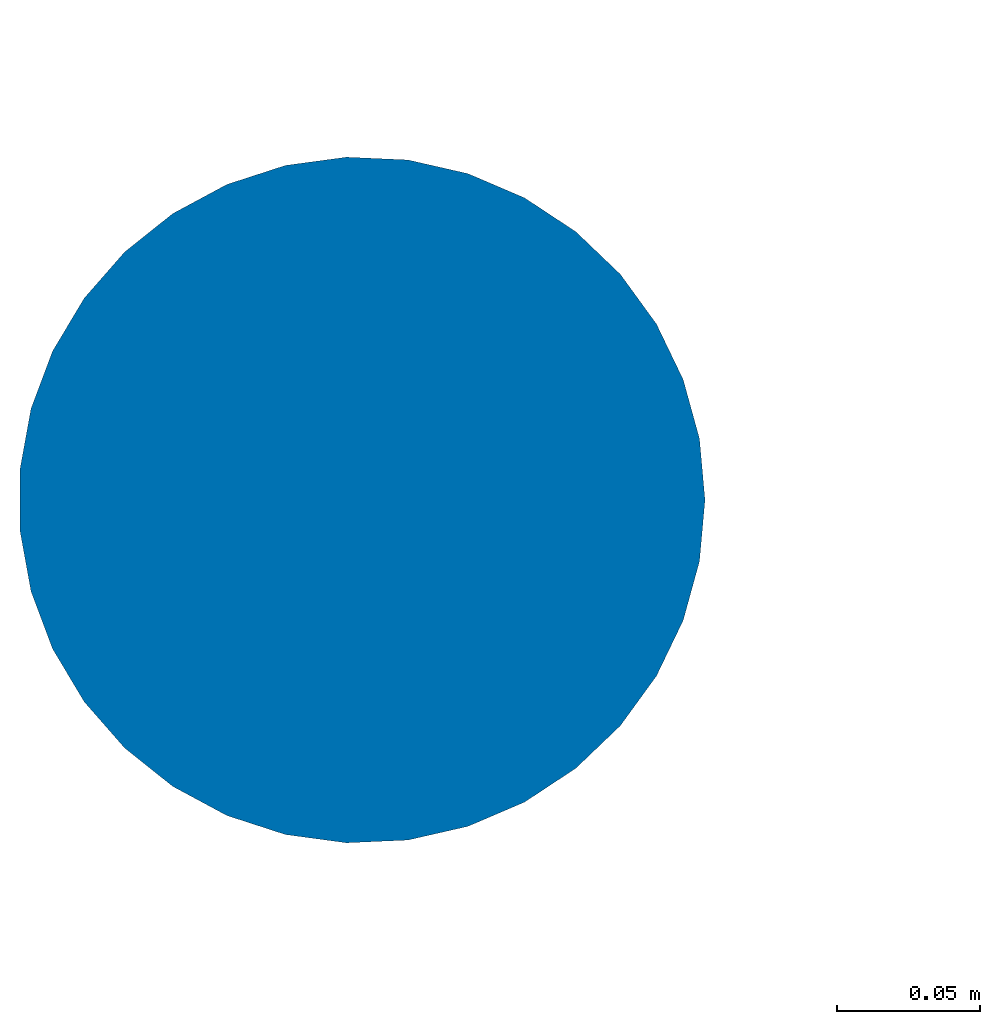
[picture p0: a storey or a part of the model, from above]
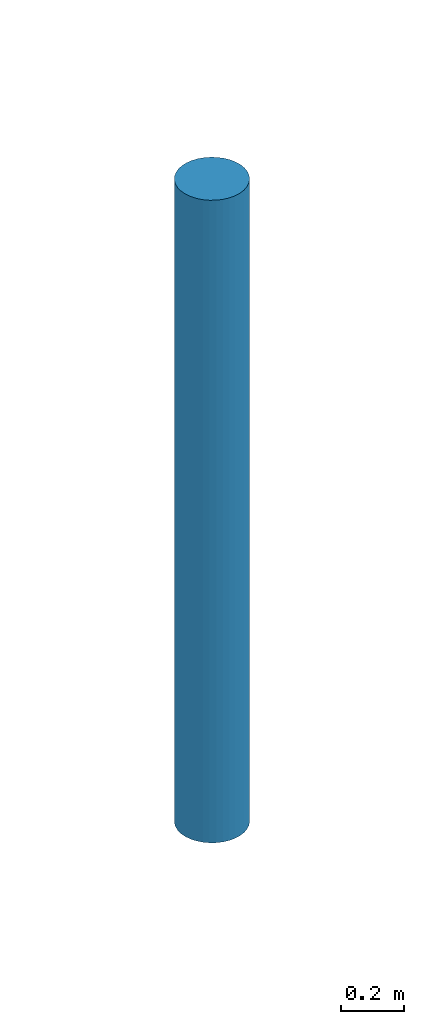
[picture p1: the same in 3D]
Properties of the parts of a building model (IFC2X3)

# File
Description: ViewDefinition [CoordinationView_V2.0, SpaceBoundary2ndLevelAddOnView], Option [Drawing Scale: 100.000000], Option [Elements to export: Visible elements (on all stories)], Option [Partial Structure Display: Entire Model], Option [IFC Domain: All], Option [Structural Function: All Elements], Option [Convert Grid elements: On], Option [Convert IFC Annotations and ARCHICAD 2D elements: Off], Option [Convert 2D symbols of Doors and Windows: Off], Option [Export geometries that Participates in Collision Detection only: Off], Option [Split complex elements: On], Option [IFC Domain For Space Containment: Custom], Option [Elements in Solid Element Operations: Extruded/revolved], Option [Elements with junctions: Extruded/revolved without junctions], Option [Slabs with slanted edge(s): Extruded], Option [IFC Site Location: At Project Origin], Option [Curtain Wall export mode: Container Element], Option [Railing export mode: Container Element], Option [Stair export mode: Container Element], Option [Properties To Export: All properties], Option [Space containment: Off], Option [Bounding Box: Off], Option [Geometry to type objects: Off], Option [Element Properties: Visible Only], Option [Building Material Properties: Off], Option [Element Parameters: Off], Option [Component Parameters: Off], Option [IFC Base Quantities: Off], Option [Door Window Parameters: On], Option [IFC Space boundaries: On], Option [ARCHICAD Zone Categories as IFC Space classification data: Off], Option [Element Classifications: On]
File name: K:\09-Projektid\3_PÕHIPROJEKT\00_Asendiplaanid\IFC\283_PP_AS_IFC_12.04.2021.ifc
Time: 2021-04-12T10:08:18
Author: Kontakti Täisnimi
Organization: Building Designer Office
Written by: The EXPRESS Data Manager Version 5.02.0100.09 : 26 Sep 2013
Made in: IFC file generated by GRAPHISOFT ARCHICAD 23.0.0 INT FULL Windows version (IFC add-on version: 4006 INT FULL).
Authorization: Kontakti Täisnimi

# IfcSite, Politse- ja Piirivalveameti ning Päästeameti ühishoone
Description: Kinnistu Kirjeldus; RefLatitude: 59, 26, 0, 0; RefLongitude: 24, 45, 0, 0; RefElevation: 0 mm; Classification: 1.0.1 IfcSite (kinnistu) (RKAS BIM + ARCHICAD Classification 23 + v 2.0)
AR_Kinnistu - 020_Pindala: 15638 m2; 025_Max_kõrgus: 18000 mm; 015_Ehitatav_pindala: 5500 m2; 010_Katastritunnus: 32213:001:0035 ja 32213:001:0036

# IfcBuilding, Politse- ja Piirivalveameti ning Päästeameti ühishoone
Classification: 1.0.2 IfcBuilding (hoone) (RKAS BIM + ARCHICAD Classification 23 + v 2.0)
AR_Hoone - 035_Sprinkler: no; 030_Hoone_aadress: Kohtla-Järve Järveküla tee 40 ja 40c; 040_Kõrgus: 8800 mm; 050_Neto_pindala: 2293.7 m2; 055_Neto_ruumala: 13540.2 m3; ?: 1820.8 m2; 001_Nimetus: Politse- ja Piirivalveameti ning Päästeameti ühishoone

# IfcBuildingStorey (2)
In: Politse- ja Piirivalveameti ning Päästeameti ühishoone
Name | Elevation (mm) | 060_Korruse_nimi | 065_Korruse_number | 070_Maapealne
Vundament | -4000 | Vundament | -1 | no
Esimene korrus | 0 | Esimene korrus | 1 | yes | Classification: 1.0.3 IfcBuildingStorey (korrus) (RKAS BIM + ARCHICAD Classification 23 + v 2.0)

# IfcBuildingElementProxy: Betoon 1200 (7)
In: Esimene korrus
Material: Betoon
AC_Pset_RenovationAndPhasing - Renovation Status: New

# IfcBuildingElementProxy: Betoon 2100, PIIRDEAED
In: Esimene korrus
Material: Betoon
AC_Pset_RenovationAndPhasing - Renovation Status: New

# IfcBuildingElementProxy: Bollard 23 (3)
In: Esimene korrus
AC_Pset_RenovationAndPhasing - Renovation Status: New

# IfcBuildingElementProxy: Door 23 (2)
In: Esimene korrus
AC_Pset_RenovationAndPhasing - Renovation Status: New

# IfcBuildingElementProxy: Grass Model 23 (64)
In: Esimene korrus
AC_Pset_RenovationAndPhasing - Renovation Status: New

# IfcBuildingElementProxy: IfcBuildingElementProxy (43149)
In: Esimene korrus
Name | Classification | Material | Renovation Status
39 x PIIRDE POST - 001 | 1.11 IfcRailing (piire) (_RKAS BIM + ARCHICAD Classification) | Teras - Konstruktsioon | Existing
77 x PIIRDE OSA - 001 | 1.11 IfcRailing (piire) (_RKAS BIM + ARCHICAD Classification) | Teras - Konstruktsioon | Existing
10760 x BALUSTER - 001 | 1.11 IfcRailing (piire) (_RKAS BIM + ARCHICAD Classification) | Teras - Konstruktsioon | Existing
126 x SISEPOST - 001 | 1.11 IfcRailing (piire) (_RKAS BIM + ARCHICAD Classification) | ET-03_Raud | Existing
44 x RAIL CONNECTION - 001 | Rail (ARCHICAD Classification) | ET-03_Raud | Existing
121 x PIIRDE OSA - 001 | 1.11 IfcRailing (piire) (_RKAS BIM + ARCHICAD Classification) | ET-03_Raud | Existing
30448 x BALUSTER - 001 | 1.11 IfcRailing (piire) (_RKAS BIM + ARCHICAD Classification) | ET-03_Raud | Existing
ÜL PIIRE - 001 | 1.11 IfcRailing (piire) (_RKAS BIM + ARCHICAD Classification) | Teras - Konstruktsioon | New
1408 x BALUSTER - 001 | 1.11 IfcRailing (piire) (_RKAS BIM + ARCHICAD Classification) | ET-06_Teras - Konstruktsioon | Existing
51 x RAIL CONNECTION - 001 | Rail (ARCHICAD Classification) | Teras - Konstruktsioon | Existing
41 x SISEPOST - 001 | 1.11 IfcRailing (piire) (_RKAS BIM + ARCHICAD Classification) | Teras - Konstruktsioon | Existing
PIIRDE OSA - 001 | 1.11 IfcRailing (piire) (_RKAS BIM + ARCHICAD Classification) | Raud | Existing
13 x RAIL CONNECTION - 001 | Rail (ARCHICAD Classification) | Iron | Existing
13 x PIIRDE OSA - 001 | 1.11 IfcRailing (piire) (_RKAS BIM + ARCHICAD Classification) | Iron | Existing
2 x HANDRAIL END - 001 | Rail (ARCHICAD Classification) | Teras - Konstruktsioon | New
2 x HANDRAIL END - 002 | Rail (ARCHICAD Classification) | Teras - Konstruktsioon | New
2 x KÄSIPUU - 001 | 1.11 IfcRailing (piire) (_RKAS BIM + ARCHICAD Classification) | Teras - Konstruktsioon | Existing

# IfcBuildingElementProxy: Landscaping_Outdoor-Furniture_CYKLOS_KAPPA-Cycle-Shelter-4-5m-8-bicycles-Sedu, VÄLISREDEL
In: Esimene korrus
AC_Pset_RenovationAndPhasing - Renovation Status: New

# IfcBuildingElementProxy: Molok Classic_ (4)
In: Esimene korrus
AC_Pset_RenovationAndPhasing - Renovation Status: New

# IfcBuildingElementProxy: Outdoor Bench 23 (2)
In: Esimene korrus
AC_Pset_RenovationAndPhasing - Renovation Status: New

# IfcBuildingElementProxy: Parking Place 23 (8)
In: Esimene korrus
AC_Pset_RenovationAndPhasing - Renovation Status: New
Name
7 x PARKIMISJOONED
PARKIMISJOON

# IfcBuildingElementProxy: Pine Tree Model 23 (14)
In: Esimene korrus
AC_Pset_RenovationAndPhasing - Renovation Status: New
Name
13 x ELUPUU
VÄLISREDEL

# IfcBuildingElementProxy: Railing Type (14)
In: Esimene korrus
AC_Pset_RenovationAndPhasing - Renovation Status: New
Name
11 x PIIRDEAED
LIUGVÄRAV
2 x KENNELI PIIRE

# IfcBuildingElementProxy: SKR-04_Puitplaat 1200 (2)
In: Esimene korrus
Material: SKR-04_Puitplaat
AC_Pset_RenovationAndPhasing - Renovation Status: New

# IfcBuildingElementProxy: Sliding Folding Multipanel Bifold Door 23 (3)
In: Esimene korrus
AC_Pset_RenovationAndPhasing - Renovation Status: New

# IfcBuildingElementProxy: Sports-Recreation_Gym-Equipment-Indoor_Draper-Inc_CM-Column-Mounted-Stationary-Basketball, Korvpallilaud
In: Esimene korrus
Classification: 1.02 IfcBuildingElementProxyType (objekt) (RKAS BIM + ARCHICAD Classification)
AR_Aken - 355_Pindala: 0 m2
Pset_BuildingElementProxyCommon - Reference: Sports-Recreation_Gym-Equipment-Indoor_Draper-Inc_CM-Column-Mounted-Stationary-Basketball
AR_001-002 - 002_Tüüp: Sports-Recreation_Gym-Equipment-Indoor_Draper-Inc_CM-Column-Mounted-Stationary-Basketball
AC_Pset_RenovationAndPhasing - Renovation Status: New

# IfcBuildingElementProxy: Tree Model Simple 1 23 (23)
In: Esimene korrus
AC_Pset_RenovationAndPhasing - Renovation Status: New

# IfcBuildingElementProxy: VKK-00_GENEERILINE - VÄLINE KESKKOND (76)
In: Esimene korrus
Material: VKK-00_GENEERILINE - VÄLINE KESKKOND
AC_Pset_RenovationAndPhasing - Renovation Status: New
Name
2 x MURU
9 x MAAPIND
5 x BETOONKIVI
30 x ÄÄREKIVI
4 x HALJASTUSKONTEINER
4 x KASVUPINNAS
4 x BETOONISTE
13 x BETOONTAKISTUS
ASFALT
Betoonäär
BETOONIST PESUPLATS
2 x TARTAAN

# IfcBuildingElementProxy: VKK-00_GENEERILINE - VÄLINE KESKKOND 20200, KÕRVALHOONE
In: Esimene korrus
Material: VKK-00_GENEERILINE - VÄLINE KESKKOND
AC_Pset_RenovationAndPhasing - Renovation Status: New

# IfcBuildingElementProxy: VKK-00_GENEERILINE - VÄLINE KESKKOND 3500, KÕRVALHOONE
In: Esimene korrus
Material: VKK-00_GENEERILINE - VÄLINE KESKKOND
AC_Pset_RenovationAndPhasing - Renovation Status: New

# IfcBuildingElementProxy: VKK-00_GENEERILINE - VÄLINE KESKKOND 6000, KÕRVALHOONE
In: Esimene korrus
Material: VKK-00_GENEERILINE - VÄLINE KESKKOND
AC_Pset_RenovationAndPhasing - Renovation Status: New

# IfcBuildingElementProxy: VKK-00_GENEERILINE - VÄLINE KESKKOND 7000, KÕRVALHOONE
In: Esimene korrus
Material: VKK-00_GENEERILINE - VÄLINE KESKKOND
AC_Pset_RenovationAndPhasing - Renovation Status: New

# IfcBuildingElementProxy: VKK-00_GENEERILINE - VÄLINE KESKKOND 750 (2)
In: Esimene korrus
Material: VKK-00_GENEERILINE - VÄLINE KESKKOND
AC_Pset_RenovationAndPhasing - Renovation Status: New

# IfcBuildingElementProxy: VKK-00_GENEERILINE - VÄLINE KESKKOND 889, KÕRVALMAAPIND
In: Esimene korrus
Material: VKK-00_GENEERILINE - VÄLINE KESKKOND
AC_Pset_RenovationAndPhasing - Renovation Status: New

# IfcColumn: ET-05_Teras D240, POST
In: Vundament
Type - PredefinedType: COLUMN
Classification: 1.03 IfcColumnType (post) (RKAS BIM + ARCHICAD Classification); Material: ET-05_Teras
Pset_ColumnCommon - Reference: ET-05; Slope: 90 deg; LoadBearing: yes; IsExternal: no
AR_001-002 - 002_Tüüp: ET-05
AC_Pset_RenovationAndPhasing - Renovation Status: New

# IfcDiscreteAccessory: Flat Panel TV 23, LED-EKRAAN
In: Esimene korrus
Classification: 1.09 IfcDiscreteAccessoryType (tarvik) (RKAS BIM + ARCHICAD Classification)
AR_001-002 - 002_Tüüp: Flat Panel TV
Pset_QuantityTakeOff - Reference: Flat Panel TV
AC_Pset_RenovationAndPhasing - Renovation Status: New

# IfcFurnishingElement: ET-05_Teras 70 x 70 (2)
In: Esimene korrus
Classification: 1.11 IfcFurnitureType (mööbel) (RKAS BIM + ARCHICAD Classification); Material: ET-05_Teras
AC_Pset_RenovationAndPhasing - Renovation Status: New

# IfcFurnishingElement: SV-00_GENEERILINE - SISEMINE VOODER 600, Tumba
In: Esimene korrus
Classification: 1.11 IfcFurnitureType (mööbel) (RKAS BIM + ARCHICAD Classification); Material: SV-00_GENEERILINE - SISEMINE VOODER
AR_Katus - 520_Pindala: 0 m2
AC_Pset_RenovationAndPhasing - Renovation Status: New

# IfcWallStandardCase: KON-00_GENEERILINE - KONSTRUKTSIOON 150, SS-01
In: Vundament
Classification: 1.24 IfcWallType (sein) (RKAS BIM + ARCHICAD Classification); Material: KON-00_GENEERILINE - KONSTRUKTSIOON 150 mm
AR_Sein - 340_Soojusläbivus: 0; 205_Tüüp: KON-00; 325_Helipidavus: R'w= 55 dB; 330_Tulekindlus: nõudeid ei esitata; 335_Välispiire: no; 376_Viimistlus_väljast: välis pind: Paint - Glossy White; sisepind: Paint - Glossy White; 505_Paksus: 150 mm; 605_Neto_pindala: 93.5637 m2; 600_Bruto_pindala: 93.5637 m2; 500_Kandev: FALSE; 376_Viimistlus_väljast (MUDELIS): KON-00_GENEERILINE - KONSTRUKTSIOON
Pset_WallCommon - Reference: KON-00; LoadBearing: no; IsExternal: no
AC_Pset_RenovationAndPhasing - Renovation Status: New

# IfcWallStandardCase: KON-00_GENEERILINE - KONSTRUKTSIOON 190 (2)
In: Esimene korrus
Classification: 1.24 IfcWallType (sein) (RKAS BIM + ARCHICAD Classification); Material: KON-00_GENEERILINE - KONSTRUKTSIOON 190 mm
Pset_WallCommon - Reference: KON-00; LoadBearing: yes; IsExternal: yes
AR_Sein - 205_Tüüp: KON-00; 325_Helipidavus: nõuded ei esitata; 330_Tulekindlus: nõudeid ei esitata; 335_Välispiire: yes; 505_Paksus: 190 mm; 500_Kandev: TRUE; 376_Viimistlus_väljast (MUDELIS): KON-00_GENEERILINE - KONSTRUKTSIOON
AC_Pset_RenovationAndPhasing - Renovation Status: New
Name | 376_Viimistlus_väljast | 605_Neto_pindala (m2) | 600_Bruto_pindala (m2)
Välissein | välis pind: RAL 010 20 10; sisepind: RAL 010 20 10 | 2.46654 | 16.0467
Välissein | välis pind: Paint - Glossy White; sisepind: Paint - Glossy White | 0 | 1.36202

# IfcWallStandardCase: KON-00_GENEERILINE - KONSTRUKTSIOON 80, Välissein
In: Esimene korrus
Classification: 1.24 IfcWallType (sein) (RKAS BIM + ARCHICAD Classification); Material: KON-00_GENEERILINE - KONSTRUKTSIOON 80 mm
Pset_WallCommon - Reference: KON-00; LoadBearing: yes; IsExternal: yes
AR_Sein - 205_Tüüp: KON-00; 325_Helipidavus: nõuded ei esitata; 330_Tulekindlus: nõudeid ei esitata; 335_Välispiire: yes; 376_Viimistlus_väljast: välis pind: Paint - Glossy White; sisepind: Paint - Glossy White; 505_Paksus: 80 mm; 605_Neto_pindala: 0.000242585 m2; 600_Bruto_pindala: 1.02525 m2; 500_Kandev: TRUE; 376_Viimistlus_väljast (MUDELIS): KON-00_GENEERILINE - KONSTRUKTSIOON
AC_Pset_RenovationAndPhasing - Renovation Status: New

# IfcWallStandardCase: SS-03_Sisesein 190 190 (2)
In: Esimene korrus
Classification: 1.24 IfcWallType (sein) (RKAS BIM + ARCHICAD Classification); Material: KON-05_Betoon Plokk - Konstuktsioon 190 mm
Pset_WallCommon - Reference: SS-03; LoadBearing: yes; IsExternal: yes
AR_Sein - 205_Tüüp: SS-03; 325_Helipidavus: nõuded ei esitata; 330_Tulekindlus: nõudeid ei esitata; 335_Välispiire: yes; 376_Viimistlus_väljast: välis pind: RAL 010 20 10; sisepind: RAL 010 20 10; 505_Paksus: 190 mm; 500_Kandev: TRUE; 376_Viimistlus_väljast (MUDELIS): KON-05_Betoon Plokk - Konstuktsioon
AC_Pset_RenovationAndPhasing - Renovation Status: New
Name | 605_Neto_pindala (m2) | 600_Bruto_pindala (m2)
Välissein | 3.44177 | 17.2223
Välissein | 2.28903 | 16.4191
